! (c) 2009  Infineon Technologies AG, Munich
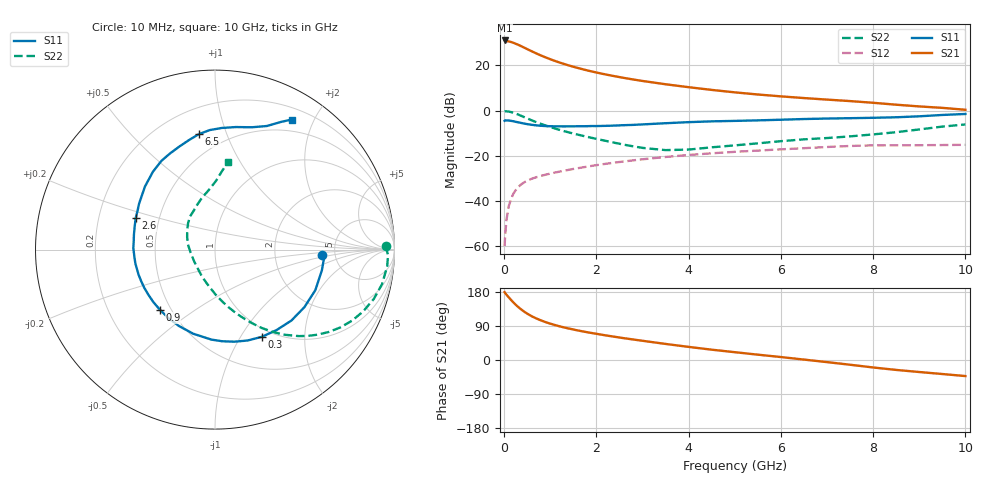
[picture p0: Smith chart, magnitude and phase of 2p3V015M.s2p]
! Infineon Technologies  Discrete & RF Semiconductors
! BFP420
! VCE =  3.0 V,  IC =  15 mA
! Common Emitter S-Parameters:  Nov 2009
# GHz  S  MA  R  50
!  f  S11  S21  S12  S22
! GHz  MAG  ANG  MAG  ANG  MAG  ANG  MAG  ANG
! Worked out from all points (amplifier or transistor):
!   46 points, 10 MHz to 10 GHz, reference 50 ohm
!   highest |S21| = 31.0 dB at 10 MHz (marker M1)
!   |S21| within 3 dB of that: start of sweep to 417 MHz
!   unconditionally stable (mu >= 1): 2.042 GHz to end of sweep
!   at 300 MHz: K = 0.26, MSG = 31.6 dB, |S12| = -34.0 dB
!   at 1.7 GHz: K = 0.92, MSG = 21.7 dB, |S12| = -25.1 dB
!   at 10 GHz: K = 1.08, MAG = 6.1 dB, |S12| = -15.1 dB
!   lowest NFmin = 1.06 dB at 900 MHz
!   S11 on the Smith chart (normalised r, x): 10 MHz: 3.92, -0.35; 300 MHz: 0.89, -1.24; 900 MHz: 0.44, -0.37; 2.6 GHz: 0.37, +0.17; 6.5 GHz: 0.36, +0.81; 10 GHz: 0.34, +1.70
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0.01  0.5961 -2.8  35.62 179.0  0.001 88.3  0.9528 1.3
0.02  0.6093 -4.4  34.7 176.7  0.0016 77.8  0.9645 -2.0
0.05  0.6066 -10.9  34.45 172.3  0.0038 82.9  0.9639 -5.6
0.1  0.6031 -22.0  33.94 165.3  0.0077 79.8  0.9504 -11.7
0.15  0.5924 -32.8  32.89 158.4  0.0111 75.9  0.9263 -17.3
0.2  0.5809 -42.9  31.65 152.0  0.0145 72.2  0.8948 -22.6
0.3  0.5516 -61.7  28.71 140.3  0.02 65.4  0.8205 -32.0
0.35  0.538 -70.3  27.2 135.3  0.0224 63.0  0.7815 -36.0
0.45  0.5122 -85.5  24.28 126.3  0.0264 58.6  0.7064 -42.9
0.6  0.4841 -104.6  20.47 115.3  0.0311 54.4  0.6078 -51.2
0.7  0.4706 -115.3  18.35 109.5  0.0336 52.7  0.5533 -55.5
0.9  0.4544 -132.4  15.01 99.8  0.0382 50.5  0.4668 -62.6
1.2  0.4479 -151.7  11.58 88.9  0.0446 49.1  0.3743 -71.6
1.7  0.4507 -174.0  8.235 75.6  0.0554 47.4  0.2773 -84.3
2.2  0.4594 169.4  6.303 65.0  0.0664 45.1  0.214 -97.4
2.6  0.4756 158.2  5.28 57.5  0.075 42.7  0.1762 -110.7
3.5  0.5254 137.9  3.823 42.4  0.0941 36.3  0.1335 -150.2
5.5  0.6075 109.1  2.271 14.1  0.1304 19.7  0.1886 145.2
6.5  0.6503 97.8  1.893 1.1  0.1473 11.2  0.231 127.1
7  0.6668 92.4  1.75 -5.6  0.1564 6.6  0.2469 118.8
8.5  0.7115 73.3  1.35 -26.2  0.1709 -9.8  0.3328 96.1
10  0.8411 59.5  1.042 -42.4  0.1749 -20.7  0.4937 81.4
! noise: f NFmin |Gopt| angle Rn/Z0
0.9  1.06  0.09  -152  0.13
1.8  1.36  0.18  -147  0.12
2.4  1.49  0.17  -148  0.14
3  1.53  0.25  -138  0.14
4  1.67  0.38  -119  0.2
5  2.14  0.44  -103  0.32
6  2.48  0.5  -88  0.47
